VERSION 5.7 ;
  NOWIREEXTENSIONATPIN ON ;
  DIVIDERCHAR "/" ;
  BUSBITCHARS "[]" ;
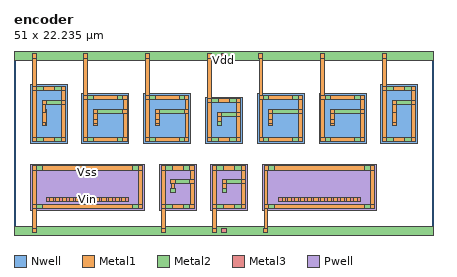
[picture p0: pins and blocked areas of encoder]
MACRO encoder
  CLASS BLOCK ;
  FOREIGN encoder ;
  ORIGIN 2.000 -7.200 ;
  SIZE 51.000 BY 22.235 ;
  PIN Vdd
    ANTENNADIFFAREA 54.005398 ;
    PORT
      LAYER Nwell ;
        RECT 0.000 18.345 4.440 25.435 ;
        RECT 6.240 18.345 11.960 24.375 ;
        RECT 13.760 18.345 19.480 24.375 ;
        RECT 21.280 18.345 25.720 23.945 ;
        RECT 27.520 18.345 33.240 24.375 ;
        RECT 35.040 18.345 40.760 24.375 ;
        RECT 42.560 18.345 47.000 25.435 ;
      LAYER Metal1 ;
        RECT 0.230 28.685 0.730 29.185 ;
        RECT 6.470 28.685 6.970 29.185 ;
        RECT 13.990 28.685 14.490 29.185 ;
        RECT 21.510 28.685 22.010 29.185 ;
        RECT 27.710 28.685 28.210 29.185 ;
        RECT 35.230 28.685 35.730 29.185 ;
        RECT 42.750 28.685 43.250 29.185 ;
        RECT 0.230 25.225 0.690 28.685 ;
        RECT 0.230 24.725 0.730 25.225 ;
        RECT 1.570 24.725 2.870 25.225 ;
        RECT 3.710 24.725 4.210 25.225 ;
        RECT 0.230 19.055 0.690 24.725 ;
        RECT 3.750 23.535 4.210 24.725 ;
        RECT 1.400 23.035 1.900 23.535 ;
        RECT 3.710 23.035 4.210 23.535 ;
        RECT 1.420 22.135 1.880 23.035 ;
        RECT 1.400 20.835 1.900 22.135 ;
        RECT 1.420 20.485 1.880 20.835 ;
        RECT 3.750 19.055 4.210 23.035 ;
        RECT 0.230 18.555 0.730 19.055 ;
        RECT 1.570 18.555 2.870 19.055 ;
        RECT 3.710 18.555 4.210 19.055 ;
        RECT 6.470 24.165 6.930 28.685 ;
        RECT 13.990 24.165 14.450 28.685 ;
        RECT 6.470 23.665 6.970 24.165 ;
        RECT 7.650 23.665 10.550 24.165 ;
        RECT 11.230 23.665 11.730 24.165 ;
        RECT 6.470 19.055 6.930 23.665 ;
        RECT 11.270 22.475 11.730 23.665 ;
        RECT 7.640 21.975 8.140 22.475 ;
        RECT 11.230 21.975 11.730 22.475 ;
        RECT 7.660 21.210 8.120 21.975 ;
        RECT 7.640 20.710 8.140 21.210 ;
        RECT 7.660 20.495 8.120 20.710 ;
        RECT 11.270 19.055 11.730 21.975 ;
        RECT 6.470 18.555 6.970 19.055 ;
        RECT 7.650 18.555 10.550 19.055 ;
        RECT 11.230 18.555 11.730 19.055 ;
        RECT 13.990 23.665 14.490 24.165 ;
        RECT 15.170 23.665 18.070 24.165 ;
        RECT 18.750 23.665 19.250 24.165 ;
        RECT 13.990 19.055 14.450 23.665 ;
        RECT 18.790 22.475 19.250 23.665 ;
        RECT 15.160 21.975 15.660 22.475 ;
        RECT 18.750 21.975 19.250 22.475 ;
        RECT 15.180 21.210 15.640 21.975 ;
        RECT 15.160 20.710 15.660 21.210 ;
        RECT 15.180 20.495 15.640 20.710 ;
        RECT 18.790 19.055 19.250 21.975 ;
        RECT 13.990 18.555 14.490 19.055 ;
        RECT 15.170 18.555 18.070 19.055 ;
        RECT 18.750 18.555 19.250 19.055 ;
        RECT 21.510 23.735 21.970 28.685 ;
        RECT 27.750 24.165 28.210 28.685 ;
        RECT 35.270 24.165 35.730 28.685 ;
        RECT 42.790 25.225 43.250 28.685 ;
        RECT 42.790 24.725 43.290 25.225 ;
        RECT 44.130 24.725 45.430 25.225 ;
        RECT 46.270 24.725 46.770 25.225 ;
        RECT 21.510 23.235 22.010 23.735 ;
        RECT 22.850 23.235 24.150 23.735 ;
        RECT 24.990 23.235 25.490 23.735 ;
        RECT 21.510 19.055 21.970 23.235 ;
        RECT 25.030 22.040 25.490 23.235 ;
        RECT 22.680 21.540 23.180 22.040 ;
        RECT 24.990 21.540 25.490 22.040 ;
        RECT 22.700 20.990 23.160 21.540 ;
        RECT 22.680 20.490 23.180 20.990 ;
        RECT 25.030 19.055 25.490 21.540 ;
        RECT 21.510 18.555 22.010 19.055 ;
        RECT 22.850 18.555 24.150 19.055 ;
        RECT 24.990 18.555 25.490 19.055 ;
        RECT 27.750 23.665 28.250 24.165 ;
        RECT 28.930 23.665 31.830 24.165 ;
        RECT 32.510 23.665 33.010 24.165 ;
        RECT 27.750 19.055 28.210 23.665 ;
        RECT 32.550 22.475 33.010 23.665 ;
        RECT 28.920 21.975 29.420 22.475 ;
        RECT 32.510 21.975 33.010 22.475 ;
        RECT 28.940 21.210 29.400 21.975 ;
        RECT 28.920 20.710 29.420 21.210 ;
        RECT 28.940 20.495 29.400 20.710 ;
        RECT 32.550 19.055 33.010 21.975 ;
        RECT 27.750 18.555 28.250 19.055 ;
        RECT 28.930 18.555 31.830 19.055 ;
        RECT 32.510 18.555 33.010 19.055 ;
        RECT 35.270 23.665 35.770 24.165 ;
        RECT 36.450 23.665 39.350 24.165 ;
        RECT 40.030 23.665 40.530 24.165 ;
        RECT 35.270 19.055 35.730 23.665 ;
        RECT 40.070 22.475 40.530 23.665 ;
        RECT 36.440 21.975 36.940 22.475 ;
        RECT 40.030 21.975 40.530 22.475 ;
        RECT 36.460 21.210 36.920 21.975 ;
        RECT 36.440 20.710 36.940 21.210 ;
        RECT 36.460 20.495 36.920 20.710 ;
        RECT 40.070 19.055 40.530 21.975 ;
        RECT 35.270 18.555 35.770 19.055 ;
        RECT 36.450 18.555 39.350 19.055 ;
        RECT 40.030 18.555 40.530 19.055 ;
        RECT 42.790 19.055 43.250 24.725 ;
        RECT 46.310 23.535 46.770 24.725 ;
        RECT 43.960 23.035 44.460 23.535 ;
        RECT 46.270 23.035 46.770 23.535 ;
        RECT 43.980 22.135 44.440 23.035 ;
        RECT 43.960 20.835 44.460 22.135 ;
        RECT 43.980 20.485 44.440 20.835 ;
        RECT 46.310 19.055 46.770 23.035 ;
        RECT 42.790 18.555 43.290 19.055 ;
        RECT 44.130 18.555 45.430 19.055 ;
        RECT 46.270 18.555 46.770 19.055 ;
      LAYER Metal2 ;
        RECT -2.000 28.435 49.000 29.435 ;
        RECT 0.230 24.725 4.210 25.225 ;
        RECT 42.790 24.725 46.770 25.225 ;
        RECT 6.470 23.665 11.730 24.165 ;
        RECT 13.990 23.665 19.250 24.165 ;
        RECT 1.400 23.035 4.210 23.535 ;
        RECT 21.510 23.235 25.490 23.735 ;
        RECT 27.750 23.665 33.010 24.165 ;
        RECT 35.270 23.665 40.530 24.165 ;
        RECT 43.960 23.035 46.770 23.535 ;
        RECT 1.400 20.485 1.900 22.485 ;
        RECT 7.640 21.975 11.730 22.475 ;
        RECT 15.160 21.975 19.250 22.475 ;
        RECT 22.680 21.540 25.490 22.040 ;
        RECT 28.920 21.975 33.010 22.475 ;
        RECT 36.440 21.975 40.530 22.475 ;
        RECT 7.640 20.495 8.140 21.425 ;
        RECT 15.160 20.495 15.660 21.425 ;
        RECT 22.680 20.490 23.180 20.990 ;
        RECT 28.920 20.495 29.420 21.425 ;
        RECT 36.440 20.495 36.940 21.425 ;
        RECT 43.960 20.485 44.460 22.485 ;
        RECT 0.230 18.555 4.210 19.055 ;
        RECT 6.470 18.555 11.730 19.055 ;
        RECT 13.990 18.555 19.250 19.055 ;
        RECT 21.510 18.555 25.490 19.055 ;
        RECT 27.750 18.555 33.010 19.055 ;
        RECT 35.270 18.555 40.530 19.055 ;
        RECT 42.790 18.555 46.770 19.055 ;
      LAYER Metal3 ;
        RECT 23.250 28.685 23.750 29.185 ;
    END
  END Vdd
  PIN Vss
    ANTENNADIFFAREA 37.930798 ;
    PORT
      LAYER Pwell ;
        RECT 0.000 10.200 13.860 15.800 ;
        RECT 15.660 10.200 20.100 15.800 ;
        RECT 21.900 10.200 26.340 15.800 ;
        RECT 28.140 10.200 42.000 15.800 ;
      LAYER Metal1 ;
        RECT 0.230 15.090 0.730 15.590 ;
        RECT 1.480 15.090 12.380 15.590 ;
        RECT 13.130 15.090 13.630 15.590 ;
        RECT 0.230 10.910 0.690 15.090 ;
        RECT 13.170 10.910 13.630 15.090 ;
        RECT 0.230 10.410 0.730 10.910 ;
        RECT 1.480 10.410 12.380 10.910 ;
        RECT 13.130 10.410 13.630 10.910 ;
        RECT 15.890 15.090 16.390 15.590 ;
        RECT 17.230 15.090 18.530 15.590 ;
        RECT 19.370 15.090 19.870 15.590 ;
        RECT 15.890 10.910 16.350 15.090 ;
        RECT 19.410 13.895 19.870 15.090 ;
        RECT 17.060 13.395 17.560 13.895 ;
        RECT 19.370 13.395 19.870 13.895 ;
        RECT 17.080 12.845 17.540 13.395 ;
        RECT 17.060 12.345 17.560 12.845 ;
        RECT 19.410 10.910 19.870 13.395 ;
        RECT 15.890 10.410 16.390 10.910 ;
        RECT 17.230 10.410 18.530 10.910 ;
        RECT 19.370 10.410 19.870 10.910 ;
        RECT 22.130 15.090 22.630 15.590 ;
        RECT 23.470 15.090 24.770 15.590 ;
        RECT 25.610 15.090 26.110 15.590 ;
        RECT 22.130 10.910 22.590 15.090 ;
        RECT 25.650 13.895 26.110 15.090 ;
        RECT 23.300 13.395 23.800 13.895 ;
        RECT 25.610 13.395 26.110 13.895 ;
        RECT 23.320 12.845 23.780 13.395 ;
        RECT 23.300 12.345 23.800 12.845 ;
        RECT 25.650 10.910 26.110 13.395 ;
        RECT 22.130 10.410 22.630 10.910 ;
        RECT 23.470 10.410 24.770 10.910 ;
        RECT 25.610 10.410 26.110 10.910 ;
        RECT 28.370 15.090 28.870 15.590 ;
        RECT 29.620 15.090 40.520 15.590 ;
        RECT 41.270 15.090 41.770 15.590 ;
        RECT 28.370 10.910 28.830 15.090 ;
        RECT 41.310 10.910 41.770 15.090 ;
        RECT 28.370 10.410 28.870 10.910 ;
        RECT 29.620 10.410 40.520 10.910 ;
        RECT 41.270 10.410 41.770 10.910 ;
        RECT 0.230 7.950 0.690 10.410 ;
        RECT 15.890 7.950 16.350 10.410 ;
        RECT 22.130 7.950 22.590 10.410 ;
        RECT 28.370 7.950 28.830 10.410 ;
        RECT 0.230 7.450 0.730 7.950 ;
        RECT 15.890 7.450 16.390 7.950 ;
        RECT 22.130 7.450 22.630 7.950 ;
        RECT 28.330 7.450 28.830 7.950 ;
      LAYER Metal2 ;
        RECT 0.230 15.090 13.630 15.590 ;
        RECT 15.890 15.090 19.870 15.590 ;
        RECT 22.130 15.090 26.110 15.590 ;
        RECT 28.370 15.090 41.770 15.590 ;
        RECT 17.060 13.395 19.870 13.895 ;
        RECT 23.300 13.395 26.110 13.895 ;
        RECT 17.060 12.345 17.560 12.845 ;
        RECT 23.300 12.345 23.800 12.845 ;
        RECT 0.230 10.410 13.630 10.910 ;
        RECT 15.890 10.410 19.870 10.910 ;
        RECT 22.130 10.410 26.110 10.910 ;
        RECT 28.370 10.410 41.770 10.910 ;
        RECT -2.000 7.200 49.000 8.200 ;
      LAYER Metal3 ;
        RECT 23.250 7.450 23.750 7.950 ;
    END
  END Vss
  PIN Vin
    ANTENNAGATEAREA 5.000000 ;
    PORT
      LAYER Metal1 ;
        RECT 2.280 11.305 2.780 11.805 ;
        RECT 3.080 11.305 3.580 11.805 ;
        RECT 3.880 11.305 4.380 11.805 ;
        RECT 4.680 11.305 5.180 11.805 ;
        RECT 5.480 11.305 5.980 11.805 ;
        RECT 6.280 11.305 6.780 11.805 ;
        RECT 7.080 11.305 7.580 11.805 ;
        RECT 7.880 11.305 8.380 11.805 ;
        RECT 8.680 11.305 9.180 11.805 ;
        RECT 9.480 11.305 9.980 11.805 ;
        RECT 10.280 11.305 10.780 11.805 ;
        RECT 11.080 11.305 11.580 11.805 ;
      LAYER Metal2 ;
<<<<<<< HEAD
        RECT 1.930 11.305 11.930 11.805 ;
      LAYER Metal3 ;
        RECT 1.930 11.305 2.430 11.805 ;
=======
        RECT 1.930 11.805 2.430 12.055 ;
        RECT 1.930 11.305 11.930 11.805 ;
>>>>>>> main
    END
  END Vin
  PIN Vin_neg
    ANTENNAGATEAREA 5.000000 ;
    PORT
      LAYER Metal1 ;
        RECT 30.420 11.305 30.920 11.805 ;
        RECT 31.220 11.305 31.720 11.805 ;
        RECT 32.020 11.305 32.520 11.805 ;
        RECT 32.820 11.305 33.320 11.805 ;
        RECT 33.620 11.305 34.120 11.805 ;
        RECT 34.420 11.305 34.920 11.805 ;
        RECT 35.220 11.305 35.720 11.805 ;
        RECT 36.020 11.305 36.520 11.805 ;
        RECT 36.820 11.305 37.320 11.805 ;
        RECT 37.620 11.305 38.120 11.805 ;
        RECT 38.420 11.305 38.920 11.805 ;
        RECT 39.220 11.305 39.720 11.805 ;
      LAYER Metal2 ;
<<<<<<< HEAD
        RECT 30.070 11.305 40.070 11.805 ;
      LAYER Metal3 ;
        RECT 30.070 11.305 30.570 11.805 ;
    END
  END Vin_neg
=======
        RECT 30.070 11.805 30.570 12.055 ;
        RECT 30.070 11.305 40.070 11.805 ;
    END
  END Vin_neg
  PIN Iex_1_i
    ANTENNADIFFAREA 0.558000 ;
    PORT
      LAYER Metal1 ;
        RECT 17.580 22.775 18.080 23.275 ;
        RECT 17.600 21.210 18.060 22.775 ;
        RECT 17.580 20.710 18.080 21.210 ;
        RECT 17.600 20.495 18.060 20.710 ;
      LAYER Metal2 ;
        RECT 15.160 22.775 18.080 23.275 ;
        RECT 17.580 20.495 18.080 21.425 ;
    END
  END Iex_1_i
  PIN Iex_2_i
    ANTENNADIFFAREA 0.558000 ;
    PORT
      LAYER Metal1 ;
        RECT 10.060 22.775 10.560 23.275 ;
        RECT 10.080 21.210 10.540 22.775 ;
        RECT 10.060 20.710 10.560 21.210 ;
        RECT 10.080 20.495 10.540 20.710 ;
      LAYER Metal2 ;
        RECT 7.640 22.775 10.560 23.275 ;
        RECT 10.060 20.495 10.560 21.425 ;
    END
  END Iex_2_i
  PIN Iex_3_i
    ANTENNADIFFAREA 0.558000 ;
    PORT
      LAYER Metal1 ;
        RECT 38.860 22.775 39.360 23.275 ;
        RECT 38.880 21.210 39.340 22.775 ;
        RECT 38.860 20.710 39.360 21.210 ;
        RECT 38.880 20.495 39.340 20.710 ;
      LAYER Metal2 ;
        RECT 36.440 22.775 39.360 23.275 ;
        RECT 38.860 20.495 39.360 21.425 ;
    END
  END Iex_3_i
  PIN Iex_4_i
    ANTENNADIFFAREA 0.558000 ;
    PORT
      LAYER Metal1 ;
        RECT 31.340 22.775 31.840 23.275 ;
        RECT 31.360 21.210 31.820 22.775 ;
        RECT 31.340 20.710 31.840 21.210 ;
        RECT 31.360 20.495 31.820 20.710 ;
      LAYER Metal2 ;
        RECT 28.920 22.775 31.840 23.275 ;
        RECT 31.340 20.495 31.840 21.425 ;
    END
  END Iex_4_i
>>>>>>> main
  OBS
      LAYER Metal1 ;
        RECT 2.540 23.835 3.040 24.335 ;
        RECT 45.100 23.835 45.600 24.335 ;
        RECT 2.560 22.135 3.020 23.835 ;
        RECT 10.060 22.775 10.560 23.275 ;
        RECT 17.580 22.775 18.080 23.275 ;
        RECT 2.540 20.835 3.040 22.135 ;
        RECT 10.080 21.210 10.540 22.775 ;
        RECT 17.600 21.210 18.060 22.775 ;
        RECT 23.820 22.340 24.320 22.840 ;
        RECT 31.340 22.775 31.840 23.275 ;
        RECT 38.860 22.775 39.360 23.275 ;
        RECT 2.560 20.485 3.020 20.835 ;
        RECT 10.060 20.710 10.560 21.210 ;
        RECT 17.580 20.710 18.080 21.210 ;
        RECT 23.840 20.990 24.300 22.340 ;
        RECT 31.360 21.210 31.820 22.775 ;
        RECT 38.880 21.210 39.340 22.775 ;
        RECT 45.120 22.135 45.580 23.835 ;
        RECT 10.080 20.495 10.540 20.710 ;
        RECT 17.600 20.495 18.060 20.710 ;
        RECT 23.820 20.490 24.320 20.990 ;
        RECT 31.340 20.710 31.840 21.210 ;
        RECT 38.860 20.710 39.360 21.210 ;
        RECT 45.100 20.835 45.600 22.135 ;
        RECT 31.360 20.495 31.820 20.710 ;
        RECT 38.880 20.495 39.340 20.710 ;
        RECT 45.120 20.485 45.580 20.835 ;
        RECT 1.970 19.445 2.470 19.945 ;
        RECT 8.450 19.450 8.950 19.950 ;
        RECT 9.250 19.450 9.750 19.950 ;
        RECT 15.970 19.450 16.470 19.950 ;
        RECT 16.770 19.450 17.270 19.950 ;
        RECT 23.250 19.450 23.750 19.950 ;
        RECT 29.730 19.450 30.230 19.950 ;
        RECT 30.530 19.450 31.030 19.950 ;
        RECT 37.250 19.450 37.750 19.950 ;
        RECT 38.050 19.450 38.550 19.950 ;
        RECT 44.530 19.445 45.030 19.945 ;
        RECT 11.960 14.195 12.460 14.695 ;
        RECT 18.200 14.195 18.700 14.695 ;
        RECT 24.440 14.195 24.940 14.695 ;
        RECT 40.100 14.195 40.600 14.695 ;
        RECT 1.400 13.395 1.900 13.895 ;
        RECT 1.420 12.845 1.880 13.395 ;
        RECT 11.980 12.845 12.440 14.195 ;
        RECT 18.220 12.845 18.680 14.195 ;
        RECT 24.460 12.845 24.920 14.195 ;
        RECT 29.540 13.395 30.040 13.895 ;
        RECT 29.560 12.845 30.020 13.395 ;
        RECT 40.120 12.845 40.580 14.195 ;
        RECT 1.400 12.345 1.900 12.845 ;
        RECT 11.960 12.345 12.460 12.845 ;
        RECT 18.200 12.345 18.700 12.845 ;
        RECT 24.440 12.345 24.940 12.845 ;
        RECT 29.540 12.345 30.040 12.845 ;
        RECT 40.100 12.345 40.600 12.845 ;
        RECT 17.630 11.305 18.130 11.805 ;
        RECT 23.870 11.305 24.370 11.805 ;
      LAYER Metal2 ;
        RECT -1.100 23.835 4.040 24.335 ;
        RECT 41.960 23.835 46.600 24.335 ;
        RECT 7.640 22.775 10.560 23.275 ;
        RECT 15.160 22.775 18.080 23.275 ;
        RECT 2.540 20.485 3.040 22.485 ;
        RECT 20.680 22.340 26.940 22.840 ;
        RECT 28.920 22.775 31.840 23.275 ;
        RECT 36.440 22.775 39.360 23.275 ;
        RECT 10.060 20.495 10.560 21.425 ;
        RECT 17.580 20.495 18.080 21.425 ;
        RECT 23.820 20.490 24.320 20.990 ;
        RECT 31.340 20.495 31.840 21.425 ;
        RECT 38.860 20.495 39.360 21.425 ;
        RECT 45.100 20.485 45.600 22.485 ;
        RECT 8.170 19.945 17.550 19.950 ;
        RECT 1.970 19.450 17.550 19.945 ;
        RECT 20.680 19.450 23.750 19.950 ;
        RECT 29.450 19.945 44.530 19.950 ;
        RECT 29.450 19.450 45.030 19.945 ;
        RECT 1.970 19.445 8.170 19.450 ;
        RECT 41.960 19.445 45.030 19.450 ;
        RECT 14.210 16.395 42.850 16.895 ;
        RECT -1.100 14.195 12.460 14.695 ;
        RECT 14.210 14.195 18.700 14.695 ;
        RECT 21.300 14.195 26.940 14.695 ;
        RECT 29.540 14.195 46.600 14.695 ;
        RECT 1.400 13.395 14.710 13.895 ;
        RECT 29.540 13.395 42.850 13.895 ;
        RECT 1.400 12.345 1.900 12.845 ;
        RECT 11.960 12.345 12.460 12.845 ;
        RECT 18.200 12.345 18.700 12.845 ;
        RECT 24.440 12.345 24.940 12.845 ;
        RECT 29.540 12.345 30.040 12.845 ;
        RECT 40.100 12.345 40.600 12.845 ;
        RECT 17.630 11.305 24.370 11.805 ;
      LAYER Metal3 ;
        RECT -1.100 14.195 -0.600 24.335 ;
        RECT 3.540 19.445 4.040 24.335 ;
        RECT 9.100 22.775 9.600 23.275 ;
        RECT 16.620 22.775 17.120 23.275 ;
        RECT 20.680 19.450 21.180 22.840 ;
        RECT 14.210 13.395 14.710 16.895 ;
        RECT 21.300 11.305 21.800 14.695 ;
        RECT 26.440 14.195 26.940 22.840 ;
        RECT 30.380 22.775 30.880 23.275 ;
        RECT 37.900 22.775 38.400 23.275 ;
        RECT 41.960 19.445 42.460 24.335 ;
        RECT 42.350 13.395 42.850 16.895 ;
        RECT 46.100 14.195 46.600 24.335 ;
  END
END encoder
END LIBRARY

